VERSION 5.7 ;
  NOWIREEXTENSIONATPIN ON ;
  DIVIDERCHAR "/" ;
  BUSBITCHARS "[]" ;
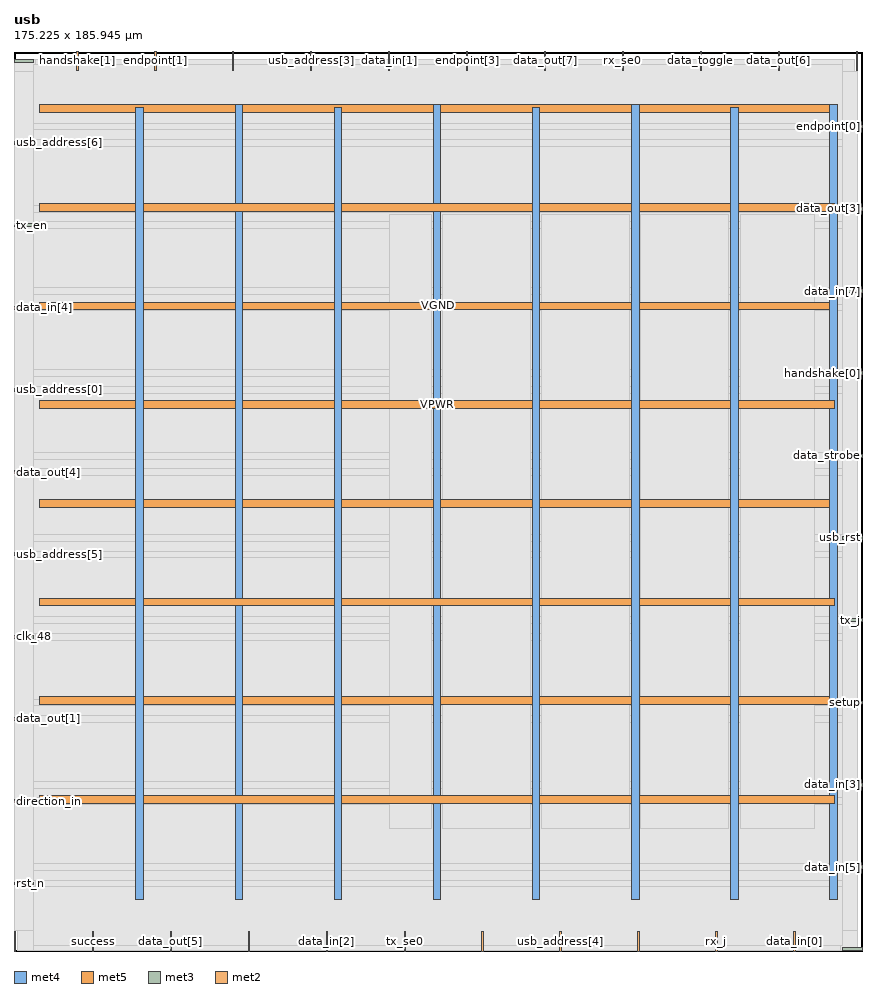
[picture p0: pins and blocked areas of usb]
MACRO usb
  CLASS BLOCK ;
  FOREIGN usb ;
  ORIGIN 0.000 0.000 ;
  SIZE 175.225 BY 185.945 ;
  PIN VGND
    DIRECTION INOUT ;
    USE GROUND ;
    PORT
      LAYER met4 ;
        RECT 45.660 10.640 47.260 174.880 ;
    END
    PORT
      LAYER met4 ;
        RECT 86.600 10.640 88.200 174.880 ;
    END
    PORT
      LAYER met4 ;
        RECT 127.540 10.640 129.140 174.880 ;
    END
    PORT
      LAYER met4 ;
        RECT 168.480 10.640 170.080 174.880 ;
    END
    PORT
      LAYER met5 ;
        RECT 5.280 50.880 170.080 52.480 ;
    END
    PORT
      LAYER met5 ;
        RECT 5.280 91.680 170.080 93.280 ;
    END
    PORT
      LAYER met5 ;
        RECT 5.280 132.480 170.080 134.080 ;
    END
    PORT
      LAYER met5 ;
        RECT 5.280 173.280 170.080 174.880 ;
    END
  END VGND
  PIN VPWR
    DIRECTION INOUT ;
    USE POWER ;
    PORT
      LAYER met4 ;
        RECT 25.190 10.640 26.790 174.320 ;
    END
    PORT
      LAYER met4 ;
        RECT 66.130 10.640 67.730 174.320 ;
    END
    PORT
      LAYER met4 ;
        RECT 107.070 10.640 108.670 174.320 ;
    END
    PORT
      LAYER met4 ;
        RECT 148.010 10.640 149.610 174.320 ;
    END
    PORT
      LAYER met5 ;
        RECT 5.280 30.480 169.520 32.080 ;
    END
    PORT
      LAYER met5 ;
        RECT 5.280 71.280 169.520 72.880 ;
    END
    PORT
      LAYER met5 ;
        RECT 5.280 112.080 169.520 113.680 ;
    END
    PORT
      LAYER met5 ;
        RECT 5.280 152.880 169.520 154.480 ;
    END
  END VPWR
  PIN clk_48
    DIRECTION INPUT ;
    USE SIGNAL ;
    PORT
      LAYER met3 ;
        RECT 0.000 64.640 4.000 65.240 ;
    END
  END clk_48
  PIN data_in[0]
    DIRECTION INPUT ;
    USE SIGNAL ;
    PORT
      LAYER met2 ;
        RECT 161.090 0.000 161.370 4.000 ;
    END
  END data_in[0]
  PIN data_in[1]
    DIRECTION INPUT ;
    USE SIGNAL ;
    PORT
      LAYER met2 ;
        RECT 77.370 181.945 77.650 185.945 ;
    END
  END data_in[1]
  PIN data_in[2]
    DIRECTION INPUT ;
    USE SIGNAL ;
    PORT
      LAYER met2 ;
        RECT 64.490 0.000 64.770 4.000 ;
    END
  END data_in[2]
  PIN data_in[3]
    DIRECTION INPUT ;
    USE SIGNAL ;
    PORT
      LAYER met3 ;
        RECT 171.225 34.040 175.225 34.640 ;
    END
  END data_in[3]
  PIN data_in[4]
    DIRECTION INPUT ;
    USE SIGNAL ;
    PORT
      LAYER met3 ;
        RECT 0.000 132.640 4.000 133.240 ;
    END
  END data_in[4]
  PIN data_in[5]
    DIRECTION INPUT ;
    USE SIGNAL ;
    PORT
      LAYER met3 ;
        RECT 171.225 17.040 175.225 17.640 ;
    END
  END data_in[5]
  PIN data_in[6]
    DIRECTION INPUT ;
    USE SIGNAL ;
    PORT
      LAYER met3 ;
        RECT 171.225 0.040 175.225 0.640 ;
    END
  END data_in[6]
  PIN data_in[7]
    DIRECTION INPUT ;
    USE SIGNAL ;
    PORT
      LAYER met3 ;
        RECT 171.225 136.040 175.225 136.640 ;
    END
  END data_in[7]
  PIN data_in_valid
    DIRECTION INPUT ;
    USE SIGNAL ;
    PORT
      LAYER met3 ;
        RECT 0.000 183.640 4.000 184.240 ;
    END
  END data_in_valid
  PIN data_out[0]
    DIRECTION OUTPUT TRISTATE ;
    USE SIGNAL ;
    PORT
      LAYER met2 ;
        RECT 96.690 0.000 96.970 4.000 ;
    END
  END data_out[0]
  PIN data_out[1]
    DIRECTION OUTPUT TRISTATE ;
    USE SIGNAL ;
    PORT
      LAYER met3 ;
        RECT 0.000 47.640 4.000 48.240 ;
    END
  END data_out[1]
  PIN data_out[2]
    DIRECTION OUTPUT TRISTATE ;
    USE SIGNAL ;
    PORT
      LAYER met2 ;
        RECT 128.890 0.000 129.170 4.000 ;
    END
  END data_out[2]
  PIN data_out[3]
    DIRECTION OUTPUT TRISTATE ;
    USE SIGNAL ;
    PORT
      LAYER met3 ;
        RECT 171.225 153.040 175.225 153.640 ;
    END
  END data_out[3]
  PIN data_out[4]
    DIRECTION OUTPUT TRISTATE ;
    USE SIGNAL ;
    PORT
      LAYER met3 ;
        RECT 0.000 98.640 4.000 99.240 ;
    END
  END data_out[4]
  PIN data_out[5]
    DIRECTION OUTPUT TRISTATE ;
    USE SIGNAL ;
    PORT
      LAYER met2 ;
        RECT 32.290 0.000 32.570 4.000 ;
    END
  END data_out[5]
  PIN data_out[6]
    DIRECTION OUTPUT TRISTATE ;
    USE SIGNAL ;
    PORT
      LAYER met2 ;
        RECT 157.870 181.945 158.150 185.945 ;
    END
  END data_out[6]
  PIN data_out[7]
    DIRECTION OUTPUT TRISTATE ;
    USE SIGNAL ;
    PORT
      LAYER met2 ;
        RECT 109.570 181.945 109.850 185.945 ;
    END
  END data_out[7]
  PIN data_strobe
    DIRECTION OUTPUT TRISTATE ;
    USE SIGNAL ;
    PORT
      LAYER met3 ;
        RECT 171.225 102.040 175.225 102.640 ;
    END
  END data_strobe
  PIN data_toggle
    DIRECTION INPUT ;
    USE SIGNAL ;
    PORT
      LAYER met2 ;
        RECT 141.770 181.945 142.050 185.945 ;
    END
  END data_toggle
  PIN direction_in
    DIRECTION OUTPUT TRISTATE ;
    USE SIGNAL ;
    PORT
      LAYER met3 ;
        RECT 0.000 30.640 4.000 31.240 ;
    END
  END direction_in
  PIN endpoint[0]
    DIRECTION OUTPUT TRISTATE ;
    USE SIGNAL ;
    PORT
      LAYER met3 ;
        RECT 171.225 170.040 175.225 170.640 ;
    END
  END endpoint[0]
  PIN endpoint[1]
    DIRECTION OUTPUT TRISTATE ;
    USE SIGNAL ;
    PORT
      LAYER met2 ;
        RECT 29.070 181.945 29.350 185.945 ;
    END
  END endpoint[1]
  PIN endpoint[2]
    DIRECTION OUTPUT TRISTATE ;
    USE SIGNAL ;
    PORT
      LAYER met2 ;
        RECT 0.090 0.000 0.370 4.000 ;
    END
  END endpoint[2]
  PIN endpoint[3]
    DIRECTION OUTPUT TRISTATE ;
    USE SIGNAL ;
    PORT
      LAYER met2 ;
        RECT 93.470 181.945 93.750 185.945 ;
    END
  END endpoint[3]
  PIN handshake[0]
    DIRECTION INPUT ;
    USE SIGNAL ;
    PORT
      LAYER met3 ;
        RECT 171.225 119.040 175.225 119.640 ;
    END
  END handshake[0]
  PIN handshake[1]
    DIRECTION INPUT ;
    USE SIGNAL ;
    PORT
      LAYER met2 ;
        RECT 12.970 181.945 13.250 185.945 ;
    END
  END handshake[1]
  PIN rst_n
    DIRECTION INPUT ;
    USE SIGNAL ;
    PORT
      LAYER met3 ;
        RECT 0.000 13.640 4.000 14.240 ;
    END
  END rst_n
  PIN rx_j
    DIRECTION INPUT ;
    USE SIGNAL ;
    PORT
      LAYER met2 ;
        RECT 144.990 0.000 145.270 4.000 ;
    END
  END rx_j
  PIN rx_se0
    DIRECTION INPUT ;
    USE SIGNAL ;
    PORT
      LAYER met2 ;
        RECT 125.670 181.945 125.950 185.945 ;
    END
  END rx_se0
  PIN setup
    DIRECTION OUTPUT TRISTATE ;
    USE SIGNAL ;
    PORT
      LAYER met3 ;
        RECT 171.225 51.040 175.225 51.640 ;
    END
  END setup
  PIN success
    DIRECTION OUTPUT TRISTATE ;
    USE SIGNAL ;
    PORT
      LAYER met2 ;
        RECT 16.190 0.000 16.470 4.000 ;
    END
  END success
  PIN transaction_active
    DIRECTION OUTPUT TRISTATE ;
    USE SIGNAL ;
    PORT
      LAYER met2 ;
        RECT 48.390 0.000 48.670 4.000 ;
    END
  END transaction_active
  PIN tx_en
    DIRECTION OUTPUT TRISTATE ;
    USE SIGNAL ;
    PORT
      LAYER met3 ;
        RECT 0.000 149.640 4.000 150.240 ;
    END
  END tx_en
  PIN tx_j
    DIRECTION OUTPUT TRISTATE ;
    USE SIGNAL ;
    PORT
      LAYER met3 ;
        RECT 171.225 68.040 175.225 68.640 ;
    END
  END tx_j
  PIN tx_se0
    DIRECTION OUTPUT TRISTATE ;
    USE SIGNAL ;
    PORT
      LAYER met2 ;
        RECT 80.590 0.000 80.870 4.000 ;
    END
  END tx_se0
  PIN usb_address[0]
    DIRECTION INPUT ;
    USE SIGNAL ;
    PORT
      LAYER met3 ;
        RECT 0.000 115.640 4.000 116.240 ;
    END
  END usb_address[0]
  PIN usb_address[1]
    DIRECTION INPUT ;
    USE SIGNAL ;
    PORT
      LAYER met2 ;
        RECT 173.970 181.945 174.250 185.945 ;
    END
  END usb_address[1]
  PIN usb_address[2]
    DIRECTION INPUT ;
    USE SIGNAL ;
    PORT
      LAYER met2 ;
        RECT 45.170 181.945 45.450 185.945 ;
    END
  END usb_address[2]
  PIN usb_address[3]
    DIRECTION INPUT ;
    USE SIGNAL ;
    PORT
      LAYER met2 ;
        RECT 61.270 181.945 61.550 185.945 ;
    END
  END usb_address[3]
  PIN usb_address[4]
    DIRECTION INPUT ;
    USE SIGNAL ;
    PORT
      LAYER met2 ;
        RECT 112.790 0.000 113.070 4.000 ;
    END
  END usb_address[4]
  PIN usb_address[5]
    DIRECTION INPUT ;
    USE SIGNAL ;
    PORT
      LAYER met3 ;
        RECT 0.000 81.640 4.000 82.240 ;
    END
  END usb_address[5]
  PIN usb_address[6]
    DIRECTION INPUT ;
    USE SIGNAL ;
    PORT
      LAYER met3 ;
        RECT 0.000 166.640 4.000 167.240 ;
    END
  END usb_address[6]
  PIN usb_rst
    DIRECTION OUTPUT TRISTATE ;
    USE SIGNAL ;
    PORT
      LAYER met3 ;
        RECT 171.225 85.040 175.225 85.640 ;
    END
  END usb_rst
  OBS
      LAYER li1 ;
        RECT 5.520 10.795 169.280 174.165 ;
      LAYER met1 ;
        RECT 0.070 10.640 174.270 174.320 ;
      LAYER met2 ;
        RECT 0.100 181.665 12.690 184.125 ;
        RECT 13.530 181.665 28.790 184.125 ;
        RECT 29.630 181.665 44.890 184.125 ;
        RECT 45.730 181.665 60.990 184.125 ;
        RECT 61.830 181.665 77.090 184.125 ;
        RECT 77.930 181.665 93.190 184.125 ;
        RECT 94.030 181.665 109.290 184.125 ;
        RECT 110.130 181.665 125.390 184.125 ;
        RECT 126.230 181.665 141.490 184.125 ;
        RECT 142.330 181.665 157.590 184.125 ;
        RECT 158.430 181.665 173.690 184.125 ;
        RECT 0.100 4.280 174.240 181.665 ;
        RECT 0.650 0.155 15.910 4.280 ;
        RECT 16.750 0.155 32.010 4.280 ;
        RECT 32.850 0.155 48.110 4.280 ;
        RECT 48.950 0.155 64.210 4.280 ;
        RECT 65.050 0.155 80.310 4.280 ;
        RECT 81.150 0.155 96.410 4.280 ;
        RECT 97.250 0.155 112.510 4.280 ;
        RECT 113.350 0.155 128.610 4.280 ;
        RECT 129.450 0.155 144.710 4.280 ;
        RECT 145.550 0.155 160.810 4.280 ;
        RECT 161.650 0.155 174.240 4.280 ;
      LAYER met3 ;
        RECT 4.400 183.240 171.225 184.105 ;
        RECT 4.000 171.040 171.225 183.240 ;
        RECT 4.000 169.640 170.825 171.040 ;
        RECT 4.000 167.640 171.225 169.640 ;
        RECT 4.400 166.240 171.225 167.640 ;
        RECT 4.000 154.040 171.225 166.240 ;
        RECT 4.000 152.640 170.825 154.040 ;
        RECT 4.000 150.640 171.225 152.640 ;
        RECT 4.400 149.240 171.225 150.640 ;
        RECT 4.000 137.040 171.225 149.240 ;
        RECT 4.000 135.640 170.825 137.040 ;
        RECT 4.000 133.640 171.225 135.640 ;
        RECT 4.400 132.240 171.225 133.640 ;
        RECT 4.000 120.040 171.225 132.240 ;
        RECT 4.000 118.640 170.825 120.040 ;
        RECT 4.000 116.640 171.225 118.640 ;
        RECT 4.400 115.240 171.225 116.640 ;
        RECT 4.000 103.040 171.225 115.240 ;
        RECT 4.000 101.640 170.825 103.040 ;
        RECT 4.000 99.640 171.225 101.640 ;
        RECT 4.400 98.240 171.225 99.640 ;
        RECT 4.000 86.040 171.225 98.240 ;
        RECT 4.000 84.640 170.825 86.040 ;
        RECT 4.000 82.640 171.225 84.640 ;
        RECT 4.400 81.240 171.225 82.640 ;
        RECT 4.000 69.040 171.225 81.240 ;
        RECT 4.000 67.640 170.825 69.040 ;
        RECT 4.000 65.640 171.225 67.640 ;
        RECT 4.400 64.240 171.225 65.640 ;
        RECT 4.000 52.040 171.225 64.240 ;
        RECT 4.000 50.640 170.825 52.040 ;
        RECT 4.000 48.640 171.225 50.640 ;
        RECT 4.400 47.240 171.225 48.640 ;
        RECT 4.000 35.040 171.225 47.240 ;
        RECT 4.000 33.640 170.825 35.040 ;
        RECT 4.000 31.640 171.225 33.640 ;
        RECT 4.400 30.240 171.225 31.640 ;
        RECT 4.000 18.040 171.225 30.240 ;
        RECT 4.000 16.640 170.825 18.040 ;
        RECT 4.000 14.640 171.225 16.640 ;
        RECT 4.400 13.240 171.225 14.640 ;
        RECT 4.000 1.040 171.225 13.240 ;
        RECT 4.000 0.175 170.825 1.040 ;
      LAYER met4 ;
        RECT 77.575 25.335 86.200 152.145 ;
        RECT 88.600 25.335 106.670 152.145 ;
        RECT 109.070 25.335 127.140 152.145 ;
        RECT 129.540 25.335 147.610 152.145 ;
        RECT 150.010 25.335 165.305 152.145 ;
  END
END usb
END LIBRARY

